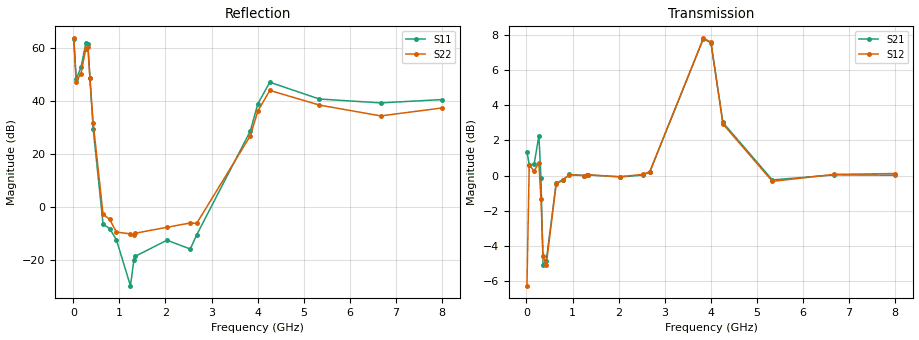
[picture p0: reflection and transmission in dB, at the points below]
!Agilent Technologies,N5230A,US43500312,A.07.50.67
!Agilent N5230A: A.07.50.67
!Date: Tuesday, June 09, 2015 15:36:15
!Correction: S11(Full 2 Port(1,2))
!S21(Full 2 Port(1,2))
!S12(Full 2 Port(1,2))
!S22(Full 2 Port(1,2))
!S2P File: Measurements: S11, S21, S12, S22:
# Hz S  MA  R 50
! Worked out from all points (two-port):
!   1601 points, 10 MHz to 8 GHz, reference 50 ohm
!   highest |S21| = 7.79 dB at 3.84 GHz (marker M1); lowest = -5.1 dB at 359.6 MHz (marker M2)
!   |S21| within 3 dB of the highest: 3.617 GHz to 4.208 GHz (590.3 MHz wide, 15.1 % of centre)
!   lowest |S11| = -29.5 dB at 1.238 GHz (marker M3), VSWR 1.07, Z = 52.5 + j2.34 ohm
!   |S11| at or under -10 dB: 810.1 MHz to 2.098 GHz (1.288 GHz wide, 88.6 % of centre); 2.44 GHz to 2.683 GHz (242.8 MHz wide, 9.48 % of centre); 3.13 GHz to 3.232 GHz (102.4 MHz wide, 3.22 % of centre)
!   |S22| runs from -14.0 to 63.6 dB; largest |S21 - S12| = 0.79
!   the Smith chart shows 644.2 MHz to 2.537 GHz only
!   S11 on the Smith chart (normalised r, x): 644.2 MHz: 0.41, +0.41; 789 MHz: 0.43, +0.04; 933.8 MHz: 1.09, -0.52; 1.313 GHz: 0.87, +0.14; 2.032 GHz: 0.61, -0.02; 2.537 GHz: 0.74, -0.13
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1e7  1497 171.1  1.17 -2.7  0.4855 -33.7  1521 -19.4
5.99375e7  256.8 326.5  1.072 1.2  1.071 -0.1  230.9 92.4
1.648062e8  431.7 402.9  1.076 8.3  1.031 4.8  329.5 124.5
2.69675e8  1221 386.6  1.298 -1.8  1.085 -9.2  969.7 103.4
3.146188e8  1208 424.5  0.9833 28.0  0.8574 20.2  1037 147.0
3.595625e8  273 442.5  0.5569 20.2  0.5899 15.6  267 176.6
4.29475e8  30.24 431.5  0.5713 15.2  0.5575 14.1  39.12 198.1
6.442062e8  0.4847 489.3  0.9516 33.8  0.9443 34.0  0.7402 381.4
7.89025e8  0.3967 534.0  0.9722 25.9  0.9706 25.6  0.593 464.7
9.338438e8  0.2455 653.4  1.007 24.9  1.005 24.8  0.3423 578.2
1.238462e9  0.03342 761.8  1 26.1  0.9996 26.2  0.3156 705.1
1.313369e9  0.09995 849.0  1.004 26.2  1.004 26.2  0.3057 750.4
1.343331e9  0.1196 852.6  1.004 26.1  1.004 26.2  0.3254 765.4
2.032469e9  0.2399 903.0  0.9904 24.5  0.9927 24.5  0.4205 1051.8
2.536838e9  0.164 930.3  1.003 27.3  1.007 27.4  0.5081 1168.2
2.676662e9  0.3021 1036.9  1.023 27.6  1.026 27.6  0.498 1225.7
3.840206e9  27.12 1411.4  2.453 25.2  2.458 25.3  22.07 1535.3
4.005e9  88.97 1404.5  2.387 5.1  2.398 5.3  64.93 1524.2
4.264675e9  226.7 1348.3  1.416 -29.1  1.403 -29.5  159.2 1459.5
5.338331e9  109.7 1325.5  0.9713 4.0  0.9624 4.2  84.49 1402.9
6.671662e9  92.68 1361.1  1.004 3.6  1.007 3.7  52.68 1342.1
8e9  107 1388.2  1.002 2.8  1.013 2.8  74.27 1309.3
